VERSION 5.7 ;
  NOWIREEXTENSIONATPIN ON ;
  DIVIDERCHAR "/" ;
  BUSBITCHARS "[]" ;
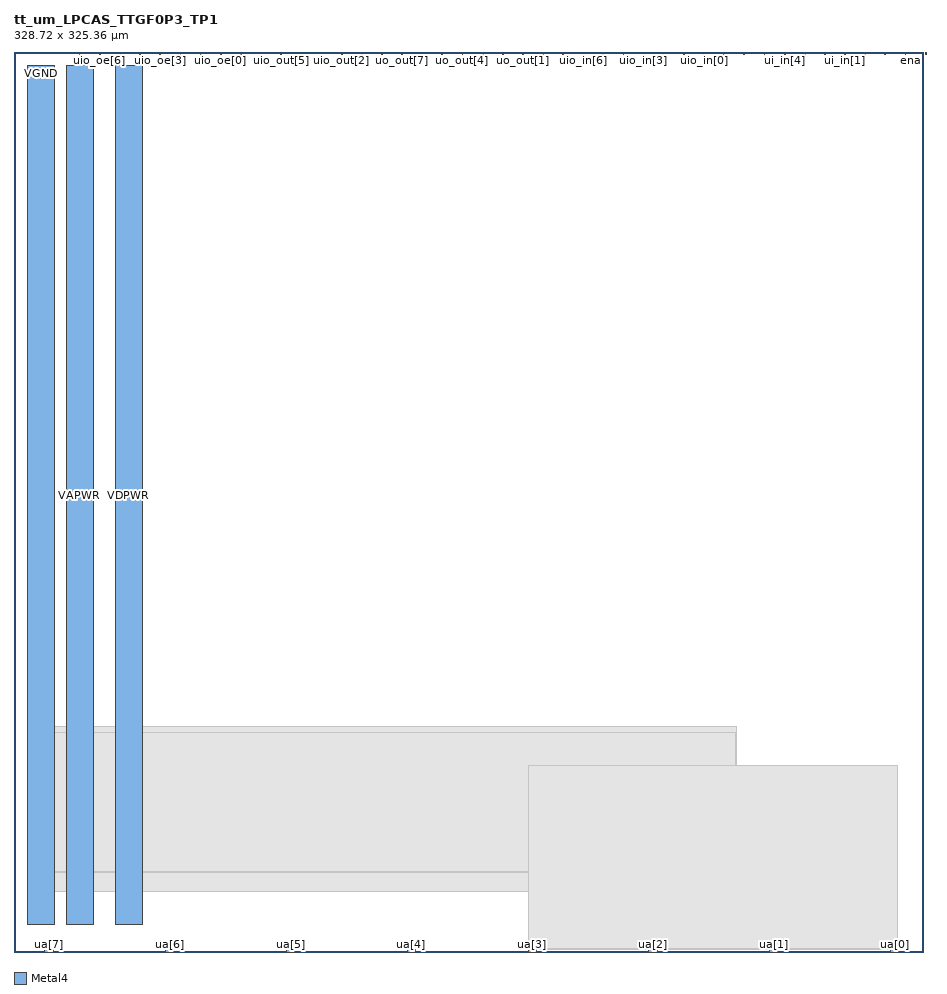
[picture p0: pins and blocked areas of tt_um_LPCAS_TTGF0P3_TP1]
MACRO tt_um_LPCAS_TTGF0P3_TP1
  CLASS BLOCK ;
  FOREIGN tt_um_LPCAS_TTGF0P3_TP1 ;
  ORIGIN 0.000 0.000 ;
  SIZE 328.720 BY 325.360 ;
  PIN clk
    PORT
      LAYER Metal4 ;
        RECT 322.130 324.360 322.430 325.360 ;
    END
  END clk
  PIN ena
    PORT
      LAYER Metal4 ;
        RECT 329.410 324.360 329.710 325.360 ;
    END
  END ena
  PIN rst_n
    PORT
      LAYER Metal4 ;
        RECT 314.850 324.360 315.150 325.360 ;
    END
  END rst_n
  PIN ui_in[0]
    PORT
      LAYER Metal4 ;
        RECT 307.570 324.360 307.870 325.360 ;
    END
  END ui_in[0]
  PIN ui_in[1]
    PORT
      LAYER Metal4 ;
        RECT 300.290 324.360 300.590 325.360 ;
    END
  END ui_in[1]
  PIN ui_in[2]
    PORT
      LAYER Metal4 ;
        RECT 293.010 324.360 293.310 325.360 ;
    END
  END ui_in[2]
  PIN ui_in[3]
    PORT
      LAYER Metal4 ;
        RECT 285.730 324.360 286.030 325.360 ;
    END
  END ui_in[3]
  PIN ui_in[4]
    PORT
      LAYER Metal4 ;
        RECT 278.450 324.360 278.750 325.360 ;
    END
  END ui_in[4]
  PIN ui_in[5]
    PORT
      LAYER Metal4 ;
        RECT 271.170 324.360 271.470 325.360 ;
    END
  END ui_in[5]
  PIN ui_in[6]
    PORT
      LAYER Metal4 ;
        RECT 263.890 324.360 264.190 325.360 ;
    END
  END ui_in[6]
  PIN ui_in[7]
    PORT
      LAYER Metal4 ;
        RECT 256.610 324.360 256.910 325.360 ;
    END
  END ui_in[7]
  PIN uio_in[0]
    PORT
      LAYER Metal4 ;
        RECT 249.330 324.360 249.630 325.360 ;
    END
  END uio_in[0]
  PIN uio_in[1]
    PORT
      LAYER Metal4 ;
        RECT 242.050 324.360 242.350 325.360 ;
    END
  END uio_in[1]
  PIN uio_in[2]
    PORT
      LAYER Metal4 ;
        RECT 234.770 324.360 235.070 325.360 ;
    END
  END uio_in[2]
  PIN uio_in[3]
    PORT
      LAYER Metal4 ;
        RECT 227.490 324.360 227.790 325.360 ;
    END
  END uio_in[3]
  PIN uio_in[4]
    PORT
      LAYER Metal4 ;
        RECT 220.210 324.360 220.510 325.360 ;
    END
  END uio_in[4]
  PIN uio_in[5]
    PORT
      LAYER Metal4 ;
        RECT 212.930 324.360 213.230 325.360 ;
    END
  END uio_in[5]
  PIN uio_in[6]
    PORT
      LAYER Metal4 ;
        RECT 205.650 324.360 205.950 325.360 ;
    END
  END uio_in[6]
  PIN uio_in[7]
    PORT
      LAYER Metal4 ;
        RECT 198.370 324.360 198.670 325.360 ;
    END
  END uio_in[7]
  PIN uo_out[0]
    PORT
      LAYER Metal4 ;
        RECT 191.090 324.360 191.390 325.360 ;
    END
  END uo_out[0]
  PIN uo_out[1]
    PORT
      LAYER Metal4 ;
        RECT 183.810 324.360 184.110 325.360 ;
    END
  END uo_out[1]
  PIN uo_out[2]
    PORT
      LAYER Metal4 ;
        RECT 176.530 324.360 176.830 325.360 ;
    END
  END uo_out[2]
  PIN uio_oe[1]
    PORT
      LAYER Metal4 ;
        RECT 67.330 324.360 67.630 325.360 ;
    END
  END uio_oe[1]
  PIN uio_oe[2]
    PORT
      LAYER Metal4 ;
        RECT 60.050 324.360 60.350 325.360 ;
    END
  END uio_oe[2]
  PIN uio_oe[3]
    PORT
      LAYER Metal4 ;
        RECT 52.770 324.360 53.070 325.360 ;
    END
  END uio_oe[3]
  PIN uio_oe[4]
    PORT
      LAYER Metal4 ;
        RECT 45.490 324.360 45.790 325.360 ;
    END
  END uio_oe[4]
  PIN uio_oe[5]
    PORT
      LAYER Metal4 ;
        RECT 38.210 324.360 38.510 325.360 ;
    END
  END uio_oe[5]
  PIN uio_oe[6]
    PORT
      LAYER Metal4 ;
        RECT 30.930 324.360 31.230 325.360 ;
    END
  END uio_oe[6]
  PIN uio_oe[7]
    PORT
      LAYER Metal4 ;
        RECT 23.650 324.360 23.950 325.360 ;
    END
  END uio_oe[7]
  PIN uio_out[0]
    PORT
      LAYER Metal4 ;
        RECT 132.850 324.360 133.150 325.360 ;
    END
  END uio_out[0]
  PIN uio_out[1]
    PORT
      LAYER Metal4 ;
        RECT 125.570 324.360 125.870 325.360 ;
    END
  END uio_out[1]
  PIN uio_out[2]
    PORT
      LAYER Metal4 ;
        RECT 118.290 324.360 118.590 325.360 ;
    END
  END uio_out[2]
  PIN uio_out[3]
    PORT
      LAYER Metal4 ;
        RECT 111.010 324.360 111.310 325.360 ;
    END
  END uio_out[3]
  PIN uio_out[4]
    PORT
      LAYER Metal4 ;
        RECT 103.730 324.360 104.030 325.360 ;
    END
  END uio_out[4]
  PIN uio_out[5]
    PORT
      LAYER Metal4 ;
        RECT 96.450 324.360 96.750 325.360 ;
    END
  END uio_out[5]
  PIN uio_out[6]
    PORT
      LAYER Metal4 ;
        RECT 89.170 324.360 89.470 325.360 ;
    END
  END uio_out[6]
  PIN uio_out[7]
    PORT
      LAYER Metal4 ;
        RECT 81.890 324.360 82.190 325.360 ;
    END
  END uio_out[7]
  PIN VGND
    USE GROUND
    ANTENNAGATEAREA 34.251999 ;
    ANTENNADIFFAREA 79.833397 ;
    PORT
      LAYER Metal4 ;
        RECT 4.815 10.000 14.815 320.360 ;
    END
  END VGND
  PIN VDPWR
    DIRECTION INOUT;
    USE POWER;
    PORT
      LAYER Metal4 ;
        RECT 36.545 10.000 46.545 320.360 ;
    END
  END VDPWR
  PIN VAPWR
    DIRECTION INOUT;
    USE POWER;
    ANTENNAGATEAREA 16.250000 ;
    ANTENNADIFFAREA 78.144997 ;
    PORT
      LAYER Metal4 ;
        RECT 18.815 10.000 28.815 320.360 ;
    END
  END VAPWR
  PIN uio_oe[0]
    PORT
      LAYER Metal4 ;
        RECT 74.610 324.360 74.910 325.360 ;
    END
  END uio_oe[0]
  PIN uo_out[3]
    PORT
      LAYER Metal4 ;
        RECT 169.250 324.360 169.550 325.360 ;
    END
  END uo_out[3]
  PIN uo_out[4]
    PORT
      LAYER Metal4 ;
        RECT 161.970 324.360 162.270 325.360 ;
    END
  END uo_out[4]
  PIN uo_out[5]
    PORT
      LAYER Metal4 ;
        RECT 154.690 324.360 154.990 325.360 ;
    END
  END uo_out[5]
  PIN uo_out[6]
    PORT
      LAYER Metal4 ;
        RECT 147.410 324.360 147.710 325.360 ;
    END
  END uo_out[6]
  PIN uo_out[7]
    PORT
      LAYER Metal4 ;
        RECT 140.130 324.360 140.430 325.360 ;
    END
  END uo_out[7]
  PIN ua[4]
    PORT
      LAYER Metal4 ;
        RECT 142.140 0.000 145.140 1.000 ;
    END
  END ua[4]
  PIN ua[5]
    PORT
      LAYER Metal4 ;
        RECT 98.460 0.000 101.460 1.000 ;
    END
  END ua[5]
  PIN ua[6]
    PORT
      LAYER Metal4 ;
        RECT 54.780 0.000 57.780 1.000 ;
    END
  END ua[6]
  PIN ua[7]
    PORT
      LAYER Metal4 ;
        RECT 11.100 0.000 14.100 1.000 ;
    END
  END ua[7]
  PIN ua[0]
    ANTENNAGATEAREA 34.000000 ;
    PORT
      LAYER Metal4 ;
        RECT 316.860 0.000 319.860 1.000 ;
    END
  END ua[0]
  PIN ua[1]
    ANTENNAGATEAREA 34.000000 ;
    PORT
      LAYER Metal4 ;
        RECT 273.180 0.000 276.180 1.000 ;
    END
  END ua[1]
  PIN ua[2]
    ANTENNAGATEAREA 84.000000 ;
    ANTENNADIFFAREA 1.220000 ;
    PORT
      LAYER Metal4 ;
        RECT 229.500 0.000 232.500 1.000 ;
    END
  END ua[2]
  PIN ua[3]
    ANTENNADIFFAREA 4.390000 ;
    PORT
      LAYER Metal4 ;
        RECT 185.820 0.000 188.820 1.000 ;
    END
  END ua[3]
  OBS
      LAYER Nwell ;
        RECT 237.765 49.155 252.985 81.390 ;
      LAYER Metal1 ;
        RECT 7.225 22.050 261.110 81.370 ;
      LAYER Metal2 ;
        RECT 8.465 28.735 261.110 79.200 ;
      LAYER Metal3 ;
        RECT 8.465 29.200 260.940 79.200 ;
      LAYER Metal4 ;
        RECT 185.820 1.300 319.240 67.600 ;
        RECT 189.120 1.000 229.200 1.300 ;
        RECT 232.800 1.000 272.880 1.300 ;
        RECT 276.480 1.000 316.560 1.300 ;
  END
END tt_um_LPCAS_TTGF0P3_TP1
END LIBRARY

